# SPDX-License-Identifier: CC0-1.0
# cc_cells: a made-up teaching cell library (not a real process; no foundry rules). Written by tools/chip/make-sample.mjs.
VERSION 5.8 ;
BUSBITCHARS "[]" ;
DIVIDERCHAR "/" ;
UNITS
  DATABASE MICRONS 1000 ;
END UNITS
MANUFACTURINGGRID 0.005 ;

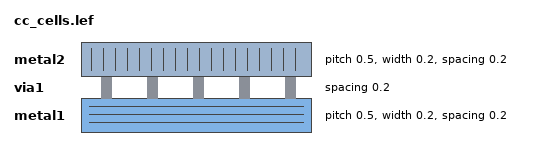
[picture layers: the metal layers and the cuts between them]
LAYER metal1
  TYPE ROUTING ;
  DIRECTION HORIZONTAL ;
  PITCH 0.5 ;
  WIDTH 0.2 ;
  SPACING 0.2 ;
END metal1

LAYER via1
  TYPE CUT ;
  SPACING 0.2 ;
END via1

LAYER metal2
  TYPE ROUTING ;
  DIRECTION VERTICAL ;
  PITCH 0.5 ;
  WIDTH 0.2 ;
  SPACING 0.2 ;
END metal2

SITE core
  CLASS CORE ;
  SYMMETRY Y ;
  SIZE 0.5 BY 4 ;
END core

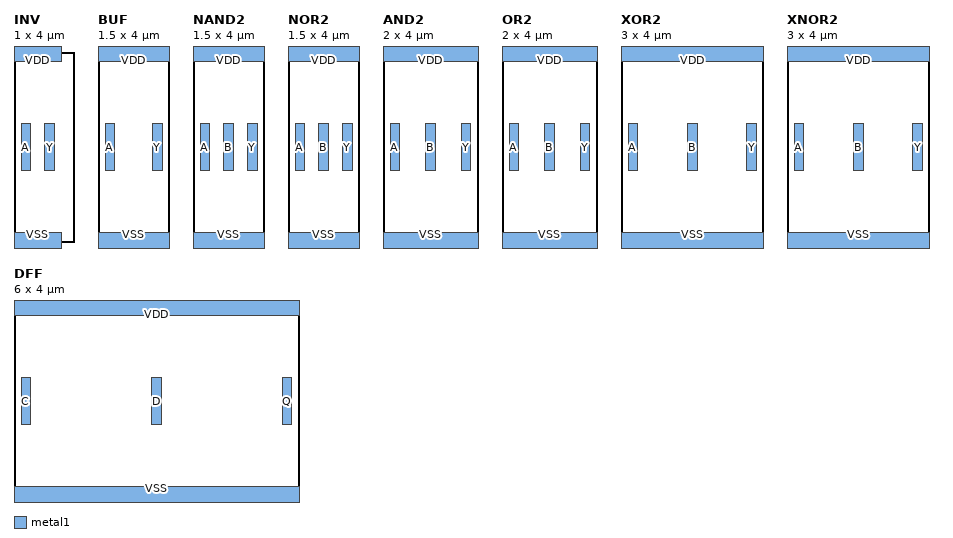
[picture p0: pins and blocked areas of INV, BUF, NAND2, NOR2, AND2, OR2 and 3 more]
MACRO INV
  CLASS CORE ;
  ORIGIN 0 0 ;
  SIZE 1 BY 4 ;
  SYMMETRY X Y ;
  SITE core ;
  PIN A
    DIRECTION INPUT ;
    USE SIGNAL ;
    PORT
      LAYER metal1 ;
        RECT 0.150 1.5 0.350 2.5 ;
    END
  END A
  PIN Y
    DIRECTION OUTPUT ;
    USE SIGNAL ;
    PORT
      LAYER metal1 ;
        RECT 0.650 1.5 0.850 2.5 ;
    END
  END Y
  PIN VDD
    DIRECTION INOUT ;
    USE POWER ;
    PORT
      LAYER metal1 ;
        RECT 0 3.8 1 4.2 ;
    END
  END VDD
  PIN VSS
    DIRECTION INOUT ;
    USE GROUND ;
    PORT
      LAYER metal1 ;
        RECT 0 -0.2 1 0.2 ;
    END
  END VSS
END INV

MACRO BUF
  CLASS CORE ;
  ORIGIN 0 0 ;
  SIZE 1.5 BY 4 ;
  SYMMETRY X Y ;
  SITE core ;
  PIN A
    DIRECTION INPUT ;
    USE SIGNAL ;
    PORT
      LAYER metal1 ;
        RECT 0.150 1.5 0.350 2.5 ;
    END
  END A
  PIN Y
    DIRECTION OUTPUT ;
    USE SIGNAL ;
    PORT
      LAYER metal1 ;
        RECT 1.150 1.5 1.350 2.5 ;
    END
  END Y
  PIN VDD
    DIRECTION INOUT ;
    USE POWER ;
    PORT
      LAYER metal1 ;
        RECT 0 3.8 1.5 4.2 ;
    END
  END VDD
  PIN VSS
    DIRECTION INOUT ;
    USE GROUND ;
    PORT
      LAYER metal1 ;
        RECT 0 -0.2 1.5 0.2 ;
    END
  END VSS
END BUF

MACRO NAND2
  CLASS CORE ;
  ORIGIN 0 0 ;
  SIZE 1.5 BY 4 ;
  SYMMETRY X Y ;
  SITE core ;
  PIN A
    DIRECTION INPUT ;
    USE SIGNAL ;
    PORT
      LAYER metal1 ;
        RECT 0.150 1.5 0.350 2.5 ;
    END
  END A
  PIN B
    DIRECTION INPUT ;
    USE SIGNAL ;
    PORT
      LAYER metal1 ;
        RECT 0.650 1.5 0.850 2.5 ;
    END
  END B
  PIN Y
    DIRECTION OUTPUT ;
    USE SIGNAL ;
    PORT
      LAYER metal1 ;
        RECT 1.150 1.5 1.350 2.5 ;
    END
  END Y
  PIN VDD
    DIRECTION INOUT ;
    USE POWER ;
    PORT
      LAYER metal1 ;
        RECT 0 3.8 1.5 4.2 ;
    END
  END VDD
  PIN VSS
    DIRECTION INOUT ;
    USE GROUND ;
    PORT
      LAYER metal1 ;
        RECT 0 -0.2 1.5 0.2 ;
    END
  END VSS
END NAND2

MACRO NOR2
  CLASS CORE ;
  ORIGIN 0 0 ;
  SIZE 1.5 BY 4 ;
  SYMMETRY X Y ;
  SITE core ;
  PIN A
    DIRECTION INPUT ;
    USE SIGNAL ;
    PORT
      LAYER metal1 ;
        RECT 0.150 1.5 0.350 2.5 ;
    END
  END A
  PIN B
    DIRECTION INPUT ;
    USE SIGNAL ;
    PORT
      LAYER metal1 ;
        RECT 0.650 1.5 0.850 2.5 ;
    END
  END B
  PIN Y
    DIRECTION OUTPUT ;
    USE SIGNAL ;
    PORT
      LAYER metal1 ;
        RECT 1.150 1.5 1.350 2.5 ;
    END
  END Y
  PIN VDD
    DIRECTION INOUT ;
    USE POWER ;
    PORT
      LAYER metal1 ;
        RECT 0 3.8 1.5 4.2 ;
    END
  END VDD
  PIN VSS
    DIRECTION INOUT ;
    USE GROUND ;
    PORT
      LAYER metal1 ;
        RECT 0 -0.2 1.5 0.2 ;
    END
  END VSS
END NOR2

MACRO AND2
  CLASS CORE ;
  ORIGIN 0 0 ;
  SIZE 2 BY 4 ;
  SYMMETRY X Y ;
  SITE core ;
  PIN A
    DIRECTION INPUT ;
    USE SIGNAL ;
    PORT
      LAYER metal1 ;
        RECT 0.150 1.5 0.350 2.5 ;
    END
  END A
  PIN B
    DIRECTION INPUT ;
    USE SIGNAL ;
    PORT
      LAYER metal1 ;
        RECT 0.900 1.5 1.100 2.5 ;
    END
  END B
  PIN Y
    DIRECTION OUTPUT ;
    USE SIGNAL ;
    PORT
      LAYER metal1 ;
        RECT 1.650 1.5 1.850 2.5 ;
    END
  END Y
  PIN VDD
    DIRECTION INOUT ;
    USE POWER ;
    PORT
      LAYER metal1 ;
        RECT 0 3.8 2 4.2 ;
    END
  END VDD
  PIN VSS
    DIRECTION INOUT ;
    USE GROUND ;
    PORT
      LAYER metal1 ;
        RECT 0 -0.2 2 0.2 ;
    END
  END VSS
END AND2

MACRO OR2
  CLASS CORE ;
  ORIGIN 0 0 ;
  SIZE 2 BY 4 ;
  SYMMETRY X Y ;
  SITE core ;
  PIN A
    DIRECTION INPUT ;
    USE SIGNAL ;
    PORT
      LAYER metal1 ;
        RECT 0.150 1.5 0.350 2.5 ;
    END
  END A
  PIN B
    DIRECTION INPUT ;
    USE SIGNAL ;
    PORT
      LAYER metal1 ;
        RECT 0.900 1.5 1.100 2.5 ;
    END
  END B
  PIN Y
    DIRECTION OUTPUT ;
    USE SIGNAL ;
    PORT
      LAYER metal1 ;
        RECT 1.650 1.5 1.850 2.5 ;
    END
  END Y
  PIN VDD
    DIRECTION INOUT ;
    USE POWER ;
    PORT
      LAYER metal1 ;
        RECT 0 3.8 2 4.2 ;
    END
  END VDD
  PIN VSS
    DIRECTION INOUT ;
    USE GROUND ;
    PORT
      LAYER metal1 ;
        RECT 0 -0.2 2 0.2 ;
    END
  END VSS
END OR2

MACRO XOR2
  CLASS CORE ;
  ORIGIN 0 0 ;
  SIZE 3 BY 4 ;
  SYMMETRY X Y ;
  SITE core ;
  PIN A
    DIRECTION INPUT ;
    USE SIGNAL ;
    PORT
      LAYER metal1 ;
        RECT 0.150 1.5 0.350 2.5 ;
    END
  END A
  PIN B
    DIRECTION INPUT ;
    USE SIGNAL ;
    PORT
      LAYER metal1 ;
        RECT 1.400 1.5 1.600 2.5 ;
    END
  END B
  PIN Y
    DIRECTION OUTPUT ;
    USE SIGNAL ;
    PORT
      LAYER metal1 ;
        RECT 2.650 1.5 2.850 2.5 ;
    END
  END Y
  PIN VDD
    DIRECTION INOUT ;
    USE POWER ;
    PORT
      LAYER metal1 ;
        RECT 0 3.8 3 4.2 ;
    END
  END VDD
  PIN VSS
    DIRECTION INOUT ;
    USE GROUND ;
    PORT
      LAYER metal1 ;
        RECT 0 -0.2 3 0.2 ;
    END
  END VSS
END XOR2

MACRO XNOR2
  CLASS CORE ;
  ORIGIN 0 0 ;
  SIZE 3 BY 4 ;
  SYMMETRY X Y ;
  SITE core ;
  PIN A
    DIRECTION INPUT ;
    USE SIGNAL ;
    PORT
      LAYER metal1 ;
        RECT 0.150 1.5 0.350 2.5 ;
    END
  END A
  PIN B
    DIRECTION INPUT ;
    USE SIGNAL ;
    PORT
      LAYER metal1 ;
        RECT 1.400 1.5 1.600 2.5 ;
    END
  END B
  PIN Y
    DIRECTION OUTPUT ;
    USE SIGNAL ;
    PORT
      LAYER metal1 ;
        RECT 2.650 1.5 2.850 2.5 ;
    END
  END Y
  PIN VDD
    DIRECTION INOUT ;
    USE POWER ;
    PORT
      LAYER metal1 ;
        RECT 0 3.8 3 4.2 ;
    END
  END VDD
  PIN VSS
    DIRECTION INOUT ;
    USE GROUND ;
    PORT
      LAYER metal1 ;
        RECT 0 -0.2 3 0.2 ;
    END
  END VSS
END XNOR2

MACRO DFF
  CLASS CORE ;
  ORIGIN 0 0 ;
  SIZE 6 BY 4 ;
  SYMMETRY X Y ;
  SITE core ;
  PIN C
    DIRECTION INPUT ;
    USE CLOCK ;
    PORT
      LAYER metal1 ;
        RECT 0.150 1.5 0.350 2.5 ;
    END
  END C
  PIN D
    DIRECTION INPUT ;
    USE SIGNAL ;
    PORT
      LAYER metal1 ;
        RECT 2.900 1.5 3.100 2.5 ;
    END
  END D
  PIN Q
    DIRECTION OUTPUT ;
    USE SIGNAL ;
    PORT
      LAYER metal1 ;
        RECT 5.650 1.5 5.850 2.5 ;
    END
  END Q
  PIN VDD
    DIRECTION INOUT ;
    USE POWER ;
    PORT
      LAYER metal1 ;
        RECT 0 3.8 6 4.2 ;
    END
  END VDD
  PIN VSS
    DIRECTION INOUT ;
    USE GROUND ;
    PORT
      LAYER metal1 ;
        RECT 0 -0.2 6 0.2 ;
    END
  END VSS
END DFF

END LIBRARY
